### For black box
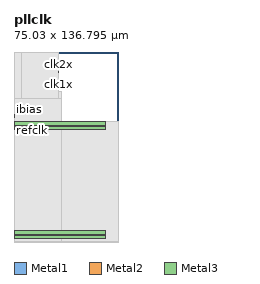
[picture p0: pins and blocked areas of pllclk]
MACRO pllclk
  CLASS BLOCK ;
  ORIGIN 0.06 0 ;
  SIZE 75.03 BY 136.795 ;
  SYMMETRY X Y R90 ;

  PIN refclk
  DIRECTION INPUT ;
    AntennaGateArea  0.039 ;
     PORT
      LAYER Metal1 ;
        RECT 0 80.115 0.15 80.305 ;
     END
  END refclk

  PIN clk1x
  DIRECTION OUTPUT ;
    ANTENNADIFFAREA 1.7285  LAYER Metal1 ;
     PORT
      LAYER Metal2 ;
        RECT 31.86 113.04 32.16 113.34 ;
     END
  END clk1x

  PIN clk2x
  DIRECTION OUTPUT ;
    ANTENNADIFFAREA 1.7285  LAYER Metal1 ;
     PORT
      LAYER Metal2 ;
        RECT 31.86 122.28 32.16 122.58 ;
     END
  END clk2x

  PIN ibias
  DIRECTION INPUT ;
    AntennaGateArea  0.039 ;
     PORT
      LAYER Metal2 ;
        RECT 0 89.95 0.3 90.25 ;
     END
  END ibias

  PIN reset
  DIRECTION INPUT ;
    AntennaGateArea  0.039 ;
     PORT
      LAYER Metal2 ;
        RECT 0 91.27 0.3 91.57 ;
     END
  END reset

  PIN vcom
  DIRECTION OUTPUT ;
    ANTENNADIFFAREA 1.7285  LAYER Metal1 ;
     PORT
      LAYER Metal2 ;
        RECT 0 87.31 0.3 87.61 ;
     END
  END vcom

  PIN vcop
  DIRECTION OUTPUT ;
    ANTENNADIFFAREA 1.7285  LAYER Metal1 ;
     PORT
      LAYER Metal2 ;
        RECT 0 88.63 0.3 88.93 ;
     END
  END vcop

  PIN agnd!
  DIRECTION INOUT ;
  USE GROUND ;
     PORT
      LAYER Metal3 ;
        RECT 0 2.39 66.14 4.89 ;
        RECT 0 2.385 0.3 4.89 ;
     END
     PORT
      LAYER Metal3 ;
        RECT 0 84.23 66.14 86.73 ;
        RECT 0 84.225 0.3 86.73 ;
     END
  END agnd!

  PIN avdd!
  DIRECTION INOUT ;
  USE POWER ;
     PORT
      LAYER Metal3 ;
        RECT 0 5.685 0.3 8.19 ;
        RECT 0 5.69 66.14 8.19 ;
     END
     PORT
      LAYER Metal3 ;
        RECT 0 80.925 0.295 83.43 ;
        RECT -0.005 80.93 66.14 83.425 ;
        RECT -0.005 80.925 0.295 83.425 ;
        RECT 0 80.93 66.14 83.43 ;
     END
  END avdd!
  OBS
      LAYER OVERLAP ;
      POLYGON	75 86.73 34.32 86.73 34.32 108.515 32.16 108.515 32.16 136.795 0 136.795 0 0 75 0 ;
      LAYER Metal1 ;
        RECT 0.07 0.07 74.93 86.66 ;
        RECT 5.315 0.07 34.25 108.445 ;
        RECT 5.315 0.07 32.09 136.725 ;
        RECT 0.07 0.07 34.25 103.06 ;
      LAYER Metal2 ;
        RECT 0.07 0.07 74.93 86.66 ;
        RECT 5.315 0.07 34.25 108.445 ;
        RECT 5.315 0.07 32.09 136.725 ;
        RECT 0.07 0.07 34.25 103.06 ;
      LAYER Metal3 ;
        RECT 0.07 0.07 54.93 86.66 ;
        RECT 5.315 0.07 34.25 108.445 ;
        RECT 5.315 0.07 32.09 136.725 ;
        RECT 0.07 0.07 34.25 103.06 ;
      LAYER Metal4 ;
        RECT 0.07 0.07 74.93 86.66 ;
        RECT 5.315 0.07 34.25 108.445 ;
        RECT 5.315 0.07 32.09 136.725 ;
        RECT 0.07 0.07 34.25 103.06 ;
      LAYER Metal5 ;
        RECT 0.07 0.07 74.93 86.66 ;
        RECT 5.315 0.07 34.25 108.445 ;
        RECT 5.315 0.07 32.09 136.725 ;
        RECT 0.07 0.07 34.25 103.06 ;
      LAYER Metal6 ;
        RECT 0.115 0.115 74.885 86.615 ;
        RECT 5.36 0.115 34.205 108.4 ;
        RECT 5.36 0.115 32.045 136.68 ;
        RECT 0.115 0.115 34.205 103.015 ;
  END
END pllclk

END LIBRARY
